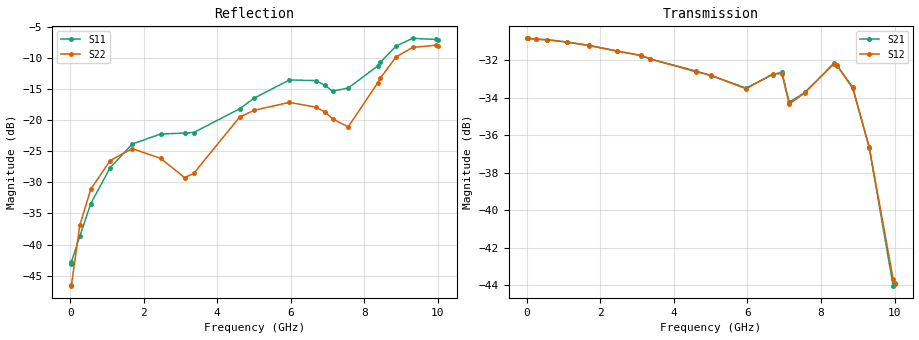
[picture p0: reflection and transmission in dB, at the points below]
! Device ID: PE43704
! Dir: z:\PE43704\PE43704_Char_1_20130516\PE43704\AMB\3p400V\30p00dB
! Serial: 14
! Insertion: A
! Impedance: 50 ohm
! Temp: Amb
! VDD: 3.400V
! Attenuation Step: 30.00dB
! IDD: 1.139999e-01mA
#  Hz  S  RI  R  50
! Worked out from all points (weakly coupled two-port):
!   401 points, 10 MHz to 10.01 GHz, reference 50 ohm
!   highest |S21| = -30.84 dB at 35 MHz (marker M1); lowest = -44.0 dB at 9.96 GHz (marker M2)
!   lowest |S11| = -43.1 dB at 10 MHz (marker M3), VSWR 1.01, Z = 50.7 + j0.0399 ohm
!   |S11| at or under -10 dB: start of sweep to 8.533 GHz
!   |S22| runs from -46.6 to -7.9 dB; largest |S21 - S12| = 0.00061
!   S11 on the Smith chart (normalised r, x): 10 MHz: 1.01, +0.00; 4.61 GHz: 0.80, +0.08; 8.435 GHz: 0.77, +0.48; 9.31 GHz: 0.51, +0.54; 10.01 GHz: 0.45, +0.33
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1e7  0.007 0.000393  0.0287 -8.92e-05  0.0287 -3.24e-05  -0.00464 0.000542
3.5e7  0.00713 0.00154  0.0287 -0.000242  0.0287 -0.000287  -0.00439 0.00185
2.6e8  0.00442 0.0108  0.0285 -0.0018  0.0285 -0.00177  -0.00609 0.0129
5.6e8  -0.00525 0.0207  0.0282 -0.00371  0.0282 -0.0037  -0.0143 0.0239
1.085e9  -0.0337 0.0239  0.0272 -0.00692  0.0272 -0.00688  -0.0376 0.0285
1.685e9  -0.0637 0.00774  0.0255 -0.0103  0.0255 -0.0102  -0.0573 0.0139
2.46e9  -0.0757 -0.015  0.0227 -0.0138  0.0227 -0.0137  -0.0492 -0.000675
3.11e9  -0.0771 -0.0153  0.02 -0.0163  0.02 -0.0164  -0.0333 0.00884
3.36e9  -0.0789 -0.00891  0.0187 -0.017  0.0188 -0.0169  -0.0332 0.017
4.61e9  -0.1116 0.0523  0.0135 -0.0192  0.0136 -0.019  -0.0863 0.0612
5.01e9  -0.1308 0.074  0.0125 -0.0191  0.0126 -0.0191  -0.1056 0.0569
5.96e9  -0.1809 0.1065  0.0089 -0.0192  0.00887 -0.0191  -0.1314 0.0442
6.685e9  -0.181 0.101  0.00781 -0.0216  0.00753 -0.0218  -0.1218 0.0352
6.935e9  -0.1631 0.0967  0.00445 -0.0229  0.00444 -0.0227  -0.1086 0.0397
7.135e9  -0.148 0.0847  0.00388 -0.019  0.00373 -0.0188  -0.0914 0.0455
7.56e9  -0.1222 0.1333  0.00445 -0.0201  0.00429 -0.0201  -0.0588 0.0656
8.36e9  -0.05 0.267  -0.00315 -0.0245  -0.00305 -0.0244  -0.0718 0.1848
8.435e9  -0.0507 0.2864  -0.00431 -0.0239  -0.00442 -0.0239  -0.0815 0.2011
8.86e9  -0.0897 0.3818  -0.00999 -0.0188  -0.0102 -0.0185  -0.1439 0.2869
9.31e9  -0.1699 0.4197  -0.00972 -0.011  -0.01 -0.0108  -0.2354 0.3019
9.96e9  -0.3064 0.3211  -0.00135 -0.00614  -0.00168 -0.00633  -0.3675 0.1558
1.001e10  -0.314 0.3019  -0.000609 -0.00632  -0.000539 -0.00637  -0.3726 0.1359
